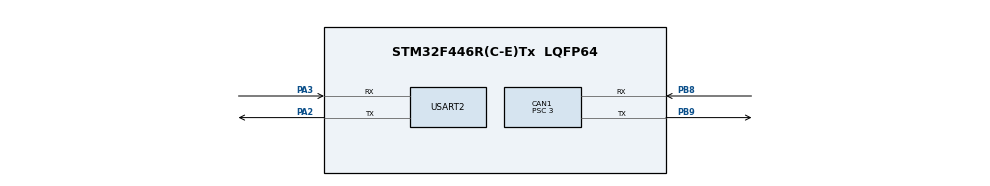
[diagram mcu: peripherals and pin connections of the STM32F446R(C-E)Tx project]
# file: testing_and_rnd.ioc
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CAN1.ABOM=ENABLE
CAN1.BS1=CAN_BS1_12TQ
CAN1.BS2=CAN_BS2_2TQ
CAN1.CalculateBaudRate=1000000
CAN1.CalculateTimeBit=1000
CAN1.CalculateTimeQuantum=66.66666666666666
CAN1.NART=ENABLE
CAN1.Prescaler=3
CAN1.SJW=CAN_SJW_1TQ
Mcu.Family=STM32F4
Mcu.Name=STM32F446R(C-E)Tx
Mcu.Package=LQFP64
NVIC.PriorityGroup=NVIC_PRIORITYGROUP_4
PA2.Mode=Asynchronous
PA2.Signal=USART2_TX
PA3.Mode=Asynchronous
PA3.Signal=USART2_RX
PB8.Mode=CAN_Activate
PB8.Signal=CAN1_RX
PB9.Mode=CAN_Activate
PB9.Signal=CAN1_TX
PH0-OSC_IN.Mode=HSE-External-Clock-Source
PH0-OSC_IN.Signal=RCC_OSC_IN
PH1-OSC_OUT.Mode=HSE-External-Clock-Source
PH1-OSC_OUT.Signal=RCC_OSC_OUT
ProjectManager.HeapSize=0x200
ProjectManager.StackSize=0x400
ProjectManager.TargetToolchain=CMake
RCC.AHBFreq_Value=180000000
RCC.APB1CLKDivider=RCC_HCLK_DIV4
RCC.APB1Freq_Value=45000000
RCC.APB1TimFreq_Value=90000000
RCC.APB2CLKDivider=RCC_HCLK_DIV2
RCC.APB2Freq_Value=90000000
RCC.APB2TimFreq_Value=180000000
RCC.CortexFreq_Value=180000000
RCC.HCLKFreq_Value=180000000
RCC.PLLM=8
RCC.PLLN=180
RCC.SYSCLKFreq_VALUE=180000000
RCC.SYSCLKSource=RCC_SYSCLKSOURCE_PLLCLK
RCC.USBFreq_Value=180000000
RCC.VCOOutputFreq_Value=360000000
USART2.VirtualMode=VM_ASYNC
board=custom

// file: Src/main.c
/* USER CODE BEGIN Header */
/**
 ******************************************************************************
 * @file           : main.c
 * @brief          : Main program body
 ******************************************************************************
 * @attention
 *
 * Copyright (c) 2026 STMicroelectronics.
 * All rights reserved.
 *
 * This software is licensed under terms that can be found in the LICENSE file
 * in the root directory of this software component.
 * If no LICENSE file comes with this software, it is provided AS-IS.
 *
 ******************************************************************************
 */
/* USER CODE END Header */
#include "main.h"
#include "can.h"
#include "gpio.h"
#include "usart.h"

/* USER CODE BEGIN Includes */
#include "app.h"
#include <stdio.h>
#include <string.h>
/* USER CODE END Includes */

void SystemClock_Config(void);

int main(void) {

    /* MCU Configuration--------------------------------------------------------*/

    /* Reset of all peripherals, Initializes the Flash interface and the Systick. */
    HAL_Init();

    /* Configure the system clock */
    SystemClock_Config();

    /* Initialize all configured peripherals */
    MX_GPIO_Init();
    if (HAL_GetDEVID() != 0x431) {
        MX_CAN1_Init();
    }
    MX_USART2_UART_Init();
    /* USER CODE BEGIN 2 */
    /* Hand over execution to Application Layer (Src/app.c).
     * CubeMX code generation preserves this single call, while all
     * application logic, state machines, and telemetry stay safe in app.c */
    app_main();
    /* USER CODE END 2 */

    /* Infinite loop */
    while (1) {

    }
}

void SystemClock_Config(void) {
    RCC_OscInitTypeDef RCC_OscInitStruct = {0};
    RCC_ClkInitTypeDef RCC_ClkInitStruct = {0};

    /** Configure the main internal regulator output voltage
     */
    __HAL_RCC_PWR_CLK_ENABLE();
    __HAL_PWR_VOLTAGESCALING_CONFIG(PWR_REGULATOR_VOLTAGE_SCALE1);

    if (HAL_GetDEVID() == 0x431) {
        /* STM32F411xC/E: Max SYSCLK is 100 MHz, no OverDrive mode */
        RCC_OscInitStruct.OscillatorType = RCC_OSCILLATORTYPE_HSI;
        RCC_OscInitStruct.HSIState = RCC_HSI_ON;
        RCC_OscInitStruct.HSICalibrationValue = RCC_HSICALIBRATION_DEFAULT;
        RCC_OscInitStruct.PLL.PLLState = RCC_PLL_ON;
        RCC_OscInitStruct.PLL.PLLSource = RCC_PLLSOURCE_HSI;
        RCC_OscInitStruct.PLL.PLLM = 16;
        RCC_OscInitStruct.PLL.PLLN = 200;
        RCC_OscInitStruct.PLL.PLLP = RCC_PLLP_DIV2;
        RCC_OscInitStruct.PLL.PLLQ = 4;
        RCC_OscInitStruct.PLL.PLLR = 2;
        if (HAL_RCC_OscConfig(&RCC_OscInitStruct) != HAL_OK) {
            Error_Handler();
        }

        RCC_ClkInitStruct.ClockType =
            RCC_CLOCKTYPE_HCLK | RCC_CLOCKTYPE_SYSCLK | RCC_CLOCKTYPE_PCLK1 | RCC_CLOCKTYPE_PCLK2;
        RCC_ClkInitStruct.SYSCLKSource = RCC_SYSCLKSOURCE_PLLCLK;
        RCC_ClkInitStruct.AHBCLKDivider = RCC_SYSCLK_DIV1;
        RCC_ClkInitStruct.APB1CLKDivider = RCC_HCLK_DIV2;
        RCC_ClkInitStruct.APB2CLKDivider = RCC_HCLK_DIV1;

        if (HAL_RCC_ClockConfig(&RCC_ClkInitStruct, FLASH_LATENCY_3) != HAL_OK) {
            Error_Handler();
        }
    } else {
        /* STM32F446xx: 180 MHz with OverDrive */
        RCC_OscInitStruct.OscillatorType = RCC_OSCILLATORTYPE_HSI;
        RCC_OscInitStruct.HSIState = RCC_HSI_ON;
        RCC_OscInitStruct.HSICalibrationValue = RCC_HSICALIBRATION_DEFAULT;
        RCC_OscInitStruct.PLL.PLLState = RCC_PLL_ON;
        RCC_OscInitStruct.PLL.PLLSource = RCC_PLLSOURCE_HSI;
        RCC_OscInitStruct.PLL.PLLM = 8;
        RCC_OscInitStruct.PLL.PLLN = 180;
        RCC_OscInitStruct.PLL.PLLP = RCC_PLLP_DIV2;
        RCC_OscInitStruct.PLL.PLLQ = 2;
        RCC_OscInitStruct.PLL.PLLR = 2;
        if (HAL_RCC_OscConfig(&RCC_OscInitStruct) != HAL_OK) {
            Error_Handler();
        }

        /** Activate the Over-Drive mode
         */
        if (HAL_PWREx_EnableOverDrive() != HAL_OK) {
            Error_Handler();
        }

        /** Initializes the CPU, AHB and APB buses clocks
         */
        RCC_ClkInitStruct.ClockType =
            RCC_CLOCKTYPE_HCLK | RCC_CLOCKTYPE_SYSCLK | RCC_CLOCKTYPE_PCLK1 | RCC_CLOCKTYPE_PCLK2;
        RCC_ClkInitStruct.SYSCLKSource = RCC_SYSCLKSOURCE_PLLCLK;
        RCC_ClkInitStruct.AHBCLKDivider = RCC_SYSCLK_DIV1;
        RCC_ClkInitStruct.APB1CLKDivider = RCC_HCLK_DIV4;
        RCC_ClkInitStruct.APB2CLKDivider = RCC_HCLK_DIV2;

        if (HAL_RCC_ClockConfig(&RCC_ClkInitStruct, FLASH_LATENCY_5) != HAL_OK) {
            Error_Handler();
        }
    }
}

/* USER CODE BEGIN 4 */
/**
 * @brief  Retargets the C library printf function to USART2 (COM3).
 */
int _write(int file, char *ptr, int len) {
    (void)file;
    HAL_UART_Transmit(&huart2, (uint8_t *)ptr, len, HAL_MAX_DELAY);
    return len;
}
/* USER CODE END 4 */

void Error_Handler(void) {
    __disable_irq();
    while (1) {
    }
}
